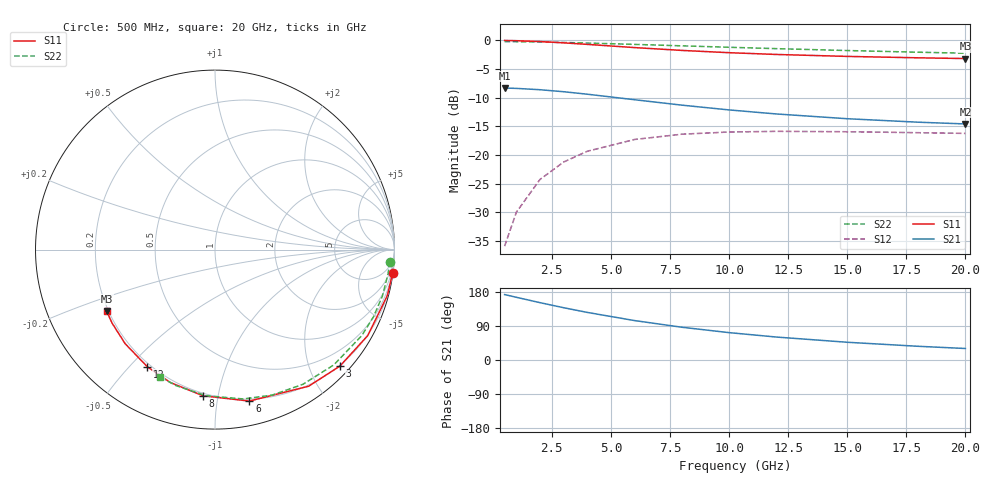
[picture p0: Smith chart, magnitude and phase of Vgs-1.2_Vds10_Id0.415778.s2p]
# Hz S RI R 50
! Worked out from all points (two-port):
!   12 points, 500 MHz to 20 GHz, reference 50 ohm
!   highest |S21| = -8.31 dB at 500 MHz (marker M1); lowest = -14.6 dB at 20 GHz (marker M2)
!   |S21| within 3 dB of the highest: start of sweep to 8.044 GHz
!   lowest |S11| = -3.2 dB at 20 GHz (marker M3), VSWR 5.54, Z = 9.63 - j12.7 ohm
!   |S11| at or under -10 dB: nowhere
!   |S22| runs from -2.2 to -0.2 dB; largest |S21 - S12| = 0.38
!   S11 on the Smith chart (normalised r, x): 500 MHz: 0, -15; 3 GHz: 0.18, -2.53; 6 GHz: 0.18, -1.24; 8 GHz: 0.18, -0.91; 12 GHz: 0.19, -0.56; 20 GHz: 0.19, -0.25
5e8  0.9899 -0.1302  -0.3809 0.0489  0.00152 0.016  0.9732 -0.0664
1e9  0.9603 -0.2561  -0.3691 0.0959  0.00598 0.0312  0.9649 -0.1321
2e9  0.8509 -0.4793  -0.3257 0.1783  0.0223 0.0572  0.9328 -0.2586
3e9  0.696 -0.6491  -0.2649 0.2389  0.0449 0.0745  0.8827 -0.3748
4e9  0.5219 -0.7611  -0.1974 0.2761  0.0693 0.0828  0.8183 -0.4785
6e9  0.1917 -0.8439  -0.0737 0.2947  0.112 0.0786  0.6623 -0.6422
8e9  -0.0659 -0.8148  0.0168 0.2719  0.1396 0.0602  0.4895 -0.7507
1e10  -0.2493 -0.7401  0.0756 0.2357  0.154 0.0391  0.3181 -0.8106
1.2e10  -0.3772 -0.6526  0.1121 0.1988  0.1598 0.0199  0.1582 -0.8322
1.5e10  -0.5004 -0.5244  0.142 0.1512  0.1598 -0.00266  -0.0495 -0.814
1.8e10  -0.5732 -0.41  0.1562 0.1142  0.1556 -0.0186  -0.2155 -0.7585
2e10  -0.6042 -0.342  0.1612 0.0944  0.1522 -0.0266  -0.3049 -0.7102
